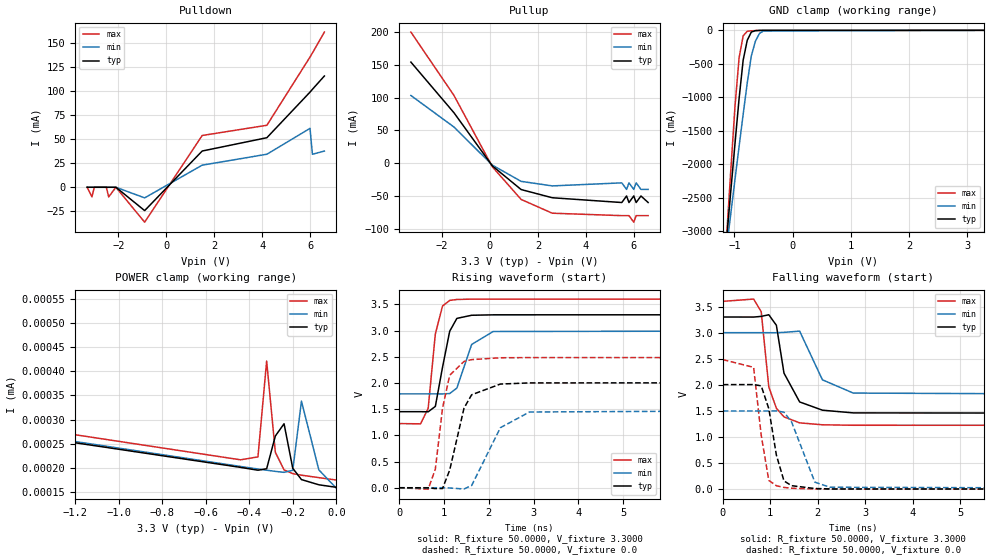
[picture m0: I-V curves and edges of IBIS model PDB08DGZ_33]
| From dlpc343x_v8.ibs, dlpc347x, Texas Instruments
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[Model]  PDB08DGZ_33
Model_type I/O
Polarity   Non-Inverting
Enable   Active-Low
Vinl =   0.8000V
Vinh =   2.0000V
Vmeas =  1.6500V
Cref =   50.0000pF
Rref =   1.0000M
Vref =   0.0V
C_comp   3.1114pF   3.0036pF   3.2323pF
[Temperature Range]   25.0000   0.1250k   -40.0000
[Voltage Range]   3.3000V   3.0000V   3.6000V
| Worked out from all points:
|   slope of the pulldown table from 0 to 0.495 V, typ, clamps not added: 29.4 ohm
|   slope of the pullup table from 0 to 0.495 V, typ, clamps not added: 26.3 ohm
|   GND clamp passes 1 mA (typ) near -0.53 V on its own axis
|   rising waveform, R_fixture 50.0000, V_fixture 3.3000: 20-80 % time 249ps typ, 299ps min, 196ps max; typ from 1.45 V to 3.3 V
|   rising waveform, R_fixture 50.0000, V_fixture 0.0: 20-80 % time 360ps typ, 548ps min, 260ps max; typ from 0 V to 2 V
|   falling waveform, R_fixture 50.0000, V_fixture 3.3000: 20-80 % time 280ps typ, 354ps min, 231ps max; typ from 3.3 V to 1.45 V
|   falling waveform, R_fixture 50.0000, V_fixture 0.0: 20-80 % time 263ps typ, 346ps min, 216ps max; typ from 2 V to 0 V
[Pulldown]
|Voltage   I(typ)   I(min)   I(max)
-3.3V     0A         0A         0A
-3.1V     0A         0A         -10mA
-3V       0A         0A         0A
-2.5V     0A         0A         0A
-2.4V     0A         0A         -10mA
-2.1V     0A         0A         0A
-900mV    -24.2mA    -11mA      -36.2mA
1.5V      37.55mA    22.89mA    53.65mA
4.2V      51.35mA    34.22mA    64.23mA
6V        98.6mA     61.04mA    134.9mA
6.1V      101.5mA    34.22mA    139.1mA
6.6V      115.3mA    37.51mA    160.8mA
[Pullup]
|Voltage   I(typ)   I(min)   I(max)
-3.3V     154.2mA    103.3mA    200mA
-1.5V     76.84mA    55.11mA    103.2mA
100mV     -4.169mA   -2.967mA   -5.57mA
1.3V      -40.19mA   -27.72mA   -55.28mA
2.6V      -52.72mA   -34.65mA   -76.29mA
5.5V      -60mA      -30mA      -80mA
5.7V      -50mA      -40mA      -80mA
5.8V      -60mA      -30mA      -80mA
6V        -50mA      -40mA      -90mA
6.1V      -60mA      -30mA      -80mA
6.3V      -50mA      -40mA      -80mA
6.6V      -60mA      -40mA      -80mA
[GND_clamp]
|Voltage   I(typ)   I(min)   I(max)
-3.3V     -25.48A    -19.05A    -34.2A
-1.13V    -3.077A    -3.219A    -3.019A
-1.06V    -2.379A    -2.721A    -2.06A
-990mV    -1.69A     -2.226A    -1.133A
-920mV    -1.02A     -1.736A    -410.7mA
-850mV    -445.7mA   -1.255A    -81.31mA
-780mV    -148.9mA   -786.8mA   -14.54mA
-710mV    -25.78mA   -382.1mA   -7.355mA
-640mV    -4.912mA   -162.5mA   -3.847mA
-570mV    -1.655mA   -46.33mA   -1.546mA
-500mV    -511uA     -8.441mA   -397.3uA
3.28V     158.3nA    192.6nA    155.2nA
[POWER_clamp]
|Voltage   I(typ)   I(min)   I(max)
-3.28V    414.4nA    400nA      887.8mA
-2.88V    365.5nA    369.3nA    885nA
-2.76V    356.6nA    360.5nA    375.2nA
-440mV    200.9nA    202.8nA    216.6nA
-360mV    195nA      197.5nA    222.7nA
-320mV    198.1nA    195nA      421.4nA
-280mV    266nA      192.6nA    232nA
-240mV    291.4nA    190.6nA    195.7nA
-200mV    199nA      194.8nA    187.9nA
-160mV    175.6nA    338.3nA    184.7nA
-80mV     164.8nA    195.7nA    179.6nA
0V        159.6nA    157.9nA    174.7nA
[Ramp]
| variable   typ   min   max
dV/dt_r  1.2024/0.3569n   0.8994/0.5482n   1.4898/0.2600n
dV/dt_f  1.1094/0.2802n   0.7254/0.3536n   1.4256/0.2310n
R_load = 50.0000
[Rising Waveform]
R_fixture= 50.0000
V_fixture= 3.3000
V_fixture_min= 3.0000
V_fixture_max= 3.6000
L_fixture= 0.0H
C_fixture= 0.0F
|time   V(typ)   V(min)   V(max)
0s        1.451V     1.791V     1.224V
480ps     1.451V     1.791V     1.219V
650ps     1.449V     1.791V     1.515V
810ps     1.552V     1.791V     2.935V
970ps     2.298V     1.79V      3.467V
1.13ns    2.986V     1.797V     3.574V
1.29ns    3.231V     1.902V     3.592V
1.62ns    3.291V     2.734V     3.599V
2.1ns     3.299V     2.981V     3.599V
16ns      3.3V       3V         3.6V
[Rising Waveform]
R_fixture= 50.0000
V_fixture= 0.0
V_fixture_min= 0.0
V_fixture_max= 0.0
L_fixture= 0.0H
C_fixture= 0.0F
|time   V(typ)   V(min)   V(max)
0s        1.985uV    2.495uV    1.822uV
650ps     -2.682mV   -1.296uV   -27.59mV
810ps     -16.65mV   -12.3uV    355.9mV
970ps     -15.18mV   107.4uV    1.517V
1.13ns    336.6mV    -5.326mV   2.146V
1.45ns    1.521V     -24.14mV   2.41V
1.62ns    1.774V     42.73mV    2.444V
2.26ns    1.978V     1.145V     2.48V
2.91ns    2V         1.445V     2.483V
16ns      2.004V     1.499V     2.483V
[Falling Waveform]
R_fixture= 50.0000
V_fixture= 3.3000
V_fixture_min= 3.0000
V_fixture_max= 3.6000
L_fixture= 0.0H
C_fixture= 0.0F
|time   V(typ)   V(min)   V(max)
0s        3.3V       3V         3.6V
650ps     3.299V     3V         3.644V
810ps     3.312V     3V         3.401V
970ps     3.343V     2.999V     1.959V
1.13ns    3.141V     2.999V     1.55V
1.29ns    2.224V     3.006V     1.386V
1.62ns    1.672V     3.029V     1.271V
2.1ns     1.514V     2.096V     1.234V
2.75ns    1.462V     1.842V     1.225V
16ns      1.451V     1.791V     1.224V
[Falling Waveform]
R_fixture= 50.0000
V_fixture= 0.0
V_fixture_min= 0.0
V_fixture_max= 0.0
L_fixture= 0.0H
C_fixture= 0.0F
|time   V(typ)   V(min)   V(max)
0s        2.004V     1.499V     2.483V
650ps     2.005V     1.499V     2.335V
810ps     1.98V      1.499V     1.034V
970ps     1.544V     1.499V     167.6mV
1.13ns    652.1mV    1.5V       66.02mV
1.29ns    157.5mV    1.476V     33.49mV
1.45ns    66.87mV    1.289V     17.87mV
1.94ns    12.68mV    134.7mV    2.833mV
2.26ns    4.823mV    36.56mV    597.7uV
16ns      0V         0V         0V
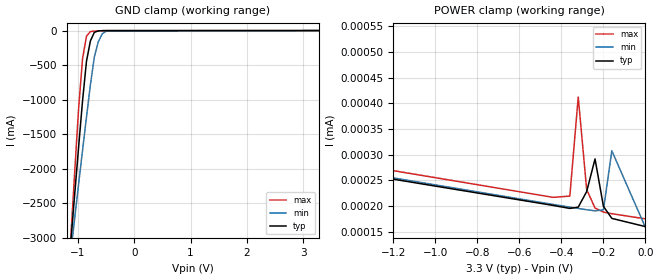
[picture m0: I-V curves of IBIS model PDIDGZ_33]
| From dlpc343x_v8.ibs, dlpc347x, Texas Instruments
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[Model]  PDIDGZ_33
Model_type Input
Polarity   Non-Inverting
Vinl =   0.8000V
Vinh =   2.0000V
C_comp   3.2674pF   3.1487pF   3.3985pF
[Temperature Range]   25.0000   0.1250k   -40.0000
[Voltage Range]   3.3000V   3.0000V   3.6000V
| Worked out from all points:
|   GND clamp passes 1 mA (typ) near -0.53 V on its own axis
[GND_clamp]
|Voltage   I(typ)   I(min)   I(max)
-3.3V     -25.48A    -19.05A    -34.2A
-1.13V    -3.077A    -3.219A    -3.019A
-1.06V    -2.379A    -2.721A    -2.06A
-990mV    -1.69A     -2.226A    -1.133A
-920mV    -1.02A     -1.736A    -410.7mA
-850mV    -445.7mA   -1.255A    -81.31mA
-780mV    -148.9mA   -786.8mA   -14.54mA
-710mV    -25.78mA   -382.1mA   -7.354mA
-640mV    -4.912mA   -162.5mA   -3.847mA
-570mV    -1.655mA   -46.33mA   -1.546mA
-500mV    -511uA     -8.441mA   -397.3uA
3.28V     158.3nA    192.5nA    155.2nA
[POWER_clamp]
|Voltage   I(typ)   I(min)   I(max)
-3.28V    414.4nA    400nA      887.8mA
-2.88V    365.5nA    369.3nA    885nA
-2.8V     359.6nA    363.4nA    386.9nA
-2.76V    356.6nA    360.5nA    375.2nA
-440mV    200.9nA    202.8nA    216.6nA
-360mV    195nA      197.5nA    219nA
-320mV    197.5nA    195nA      412nA
-280mV    227.7nA    192.5nA    232nA
-240mV    291.4nA    190.3nA    195.7nA
-200mV    199nA      192.2nA    187.9nA
-160mV    175.6nA    307.3nA    184.7nA
0V        159.6nA    157.9nA    174.7nA
